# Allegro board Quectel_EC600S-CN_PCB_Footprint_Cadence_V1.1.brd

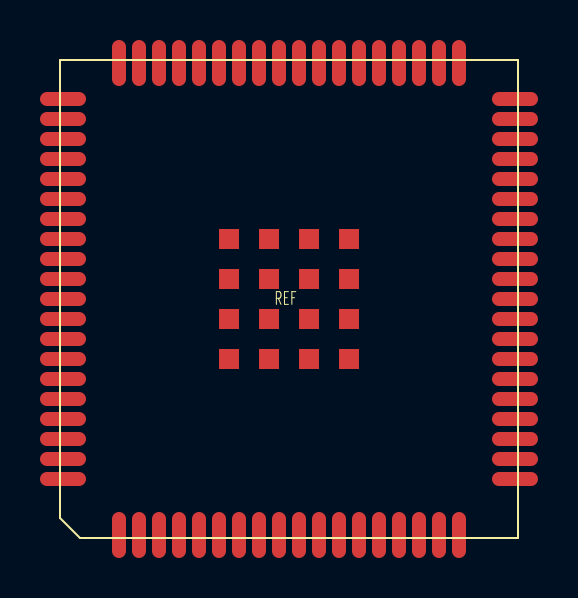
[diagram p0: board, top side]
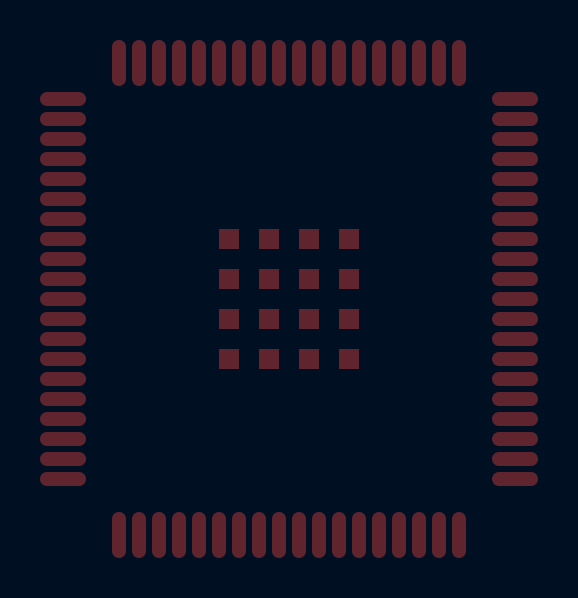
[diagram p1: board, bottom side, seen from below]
No outline. copper layers: TOP, BOTTOM. Coordinates in mm from the lowest, leftmost part position.

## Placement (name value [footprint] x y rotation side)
REF  -  [unnamed]  0 0 0 top

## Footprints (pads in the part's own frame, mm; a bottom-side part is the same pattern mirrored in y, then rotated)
unnamed
  oval 0.7x2.3 smd: 1(-8.5,-11.8) 2(-7.5,-11.8) 3(-6.5,-11.8) 4(-5.5,-11.8) 5(-4.5,-11.8) 6(-3.5,-11.8) 7(-2.5,-11.8) 8(-1.5,-11.8) 9(-0.5,-11.8) 10(0.5,-11.8) 11(1.5,-11.8) 12(2.5,-11.8) 13(3.5,-11.8) 14(4.5,-11.8) 15(5.5,-11.8) 16(6.5,-11.8) 17(7.5,-11.8) 18(8.5,-11.8) 39(8.5,11.8) 40(7.5,11.8) 41(6.5,11.8) 42(5.5,11.8) 43(4.5,11.8) 44(3.5,11.8) 45(2.5,11.8) 46(1.5,11.8) 47(0.5,11.8) 48(-0.5,11.8) 49(-1.5,11.8) 50(-2.5,11.8) 51(-3.5,11.8) 52(-4.5,11.8) 53(-5.5,11.8) 54(-6.5,11.8) 55(-7.5,11.8) 56(-8.5,11.8)
  oval 2.3x0.7 smd: 19(11.3,-9) 20(11.3,-8) 21(11.3,-7) 22(11.3,-6) 23(11.3,-5) 24(11.3,-4) 25(11.3,-3) 26(11.3,-2) 27(11.3,-1) 28(11.3,0) 29(11.3,1) 30(11.3,2) 31(11.3,3) 32(11.3,4) 33(11.3,5) 34(11.3,6) 35(11.3,7) 36(11.3,8) 37(11.3,9) 38(11.3,10) 57(-11.3,10) 58(-11.3,9) 59(-11.3,8) 60(-11.3,7) 61(-11.3,6) 62(-11.3,5) 63(-11.3,4) 64(-11.3,3) 65(-11.3,2) 66(-11.3,1) 67(-11.3,0) 68(-11.3,-1) 69(-11.3,-2) 70(-11.3,-3) 71(-11.3,-4) 72(-11.3,-5) 73(-11.3,-6) 74(-11.3,-7) 75(-11.3,-8) 76(-11.3,-9)
  rect 1x1 smd: 77(-3,-3) 78(-1,-3) 79(1,-3) 80(3,-3) 81(3,-1) 82(3,1) 83(3,3) 84(1,3) 85(-1,3) 86(-3,3) 87(-3,1) 88(-3,-1) 89(-1,-1) 90(1,-1) 91(1,1) 92(-1,1)

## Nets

Pads without a net: REF 1 2 3 4 5 6 7 8 9 10 11 12 13 14 15 16 17 18 19 20 21 22 23 24 25 26 27 28 29 30 31 32 33 34 35 36 37 38 39 40 41 42 43 44 45 46 47 48 49 50 51 52 53 54 55 56 57 58 59 60 61 62 63 64 65 66 67 68 69 70 71 72 73 74 75 76 77 78 79 80 81 82 83 84 85 86 87 88 89 90 91 92
